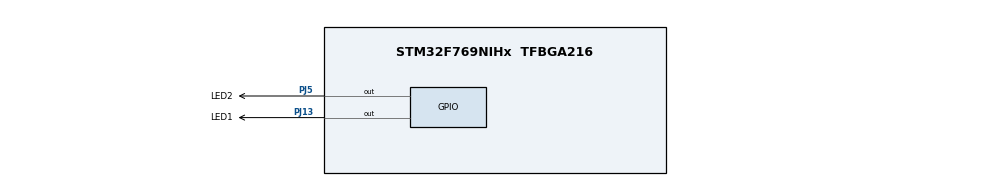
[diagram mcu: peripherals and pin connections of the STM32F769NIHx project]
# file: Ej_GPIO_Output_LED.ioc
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CORTEX_M7.ART_ACCLERATOR_ENABLE=0
CORTEX_M7.CPU_DCache=Disabled
CORTEX_M7.CPU_ICache=Disabled
CORTEX_M7.PREFETCH_ENABLE=0
Mcu.Family=STM32F7
Mcu.Name=STM32F769NIHx
Mcu.Package=TFBGA216
NVIC.PriorityGroup=NVIC_PRIORITYGROUP_4
NVIC.RCC_IRQn=true\:0\:0\:false\:false\:true\:true
PH0/OSC_IN.Mode=HSE-External-Oscillator
PH0/OSC_IN.Signal=RCC_OSC_IN
PH1/OSC_OUT.Mode=HSE-External-Oscillator
PH1/OSC_OUT.Signal=RCC_OSC_OUT
PJ13.GPIO_Label=LED1
PJ13.Signal=GPIO_Output
PJ5.GPIO_Label=LED2
PJ5.Signal=GPIO_Output
ProjectManager.HeapSize=0x200
ProjectManager.StackSize=0x400
ProjectManager.TargetToolchain=MDK-ARM V5
RCC.AHBFreq_Value=216000000
RCC.APB1CLKDivider=RCC_HCLK_DIV4
RCC.APB1Freq_Value=54000000
RCC.APB1TimFreq_Value=108000000
RCC.APB2CLKDivider=RCC_HCLK_DIV2
RCC.APB2Freq_Value=108000000
RCC.APB2TimFreq_Value=216000000
RCC.CortexFreq_Value=216000000
RCC.HCLKFreq_Value=216000000
RCC.HSE_VALUE=4000000
RCC.HSI_VALUE=16000000
RCC.LSE_VALUE=32768
RCC.PLL48CLockSelection=RCC_CLK48SOURCE_PLLSAIP
RCC.PLLDSIIDF=DSI_PLL_IN_DIV2
RCC.PLLDSINDIV=125
RCC.PLLI2SN=96
RCC.PLLM=2
RCC.PLLN=216
RCC.PLLQ=4
RCC.PLLSAIN=108
RCC.PLLSAIP=RCC_PLLSAIP_DIV6
RCC.PLLSAIQ=3
RCC.PLLSAIR=3
RCC.PLLSourceVirtual=RCC_PLLSOURCE_HSE
RCC.PLLState-ClockTree=RCC_PLL_ON
RCC.SDMMC2ClockSelection=RCC_SDMMC2CLKSOURCE_CLK48
RCC.SYSCLKFreq_VALUE=216000000
RCC.SYSCLKSource=RCC_SYSCLKSOURCE_PLLCLK
RCC.USBFreq_Value=36000000
RCC.VCOOutputFreq_Value=432000000
board=32F769IDISCOVERY

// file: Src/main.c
/**
  ******************************************************************************
  * @file           : main.c
  * @brief          : Main program body
  ******************************************************************************
  ** This notice applies to any and all portions of this file
  * that are not between comment pairs USER CODE BEGIN and
  * USER CODE END. Other portions of this file, whether
  * inserted by the user or by software development tools
  * are owned by their respective copyright owners.
  *
  * COPYRIGHT(c) 2018 STMicroelectronics
  *
  * Redistribution and use in source and binary forms, with or without modification,
  * are permitted provided that the following conditions are met:
  *   1. Redistributions of source code must retain the above copyright notice,
  *      this list of conditions and the following disclaimer.
  *   2. Redistributions in binary form must reproduce the above copyright notice,
  *      this list of conditions and the following disclaimer in the documentation
  *      and/or other materials provided with the distribution.
  *   3. Neither the name of STMicroelectronics nor the names of its contributors
  *      may be used to endorse or promote products derived from this software
  *      without specific prior written permission.
  *
  * THIS SOFTWARE IS PROVIDED BY THE COPYRIGHT HOLDERS AND CONTRIBUTORS "AS IS"
  * AND ANY EXPRESS OR IMPLIED WARRANTIES, INCLUDING, BUT NOT LIMITED TO, THE
  * IMPLIED WARRANTIES OF MERCHANTABILITY AND FITNESS FOR A PARTICULAR PURPOSE ARE
  * DISCLAIMED. IN NO EVENT SHALL THE COPYRIGHT HOLDER OR CONTRIBUTORS BE LIABLE
  * FOR ANY DIRECT, INDIRECT, INCIDENTAL, SPECIAL, EXEMPLARY, OR CONSEQUENTIAL
  * DAMAGES (INCLUDING, BUT NOT LIMITED TO, PROCUREMENT OF SUBSTITUTE GOODS OR
  * SERVICES; LOSS OF USE, DATA, OR PROFITS; OR BUSINESS INTERRUPTION) HOWEVER
  * CAUSED AND ON ANY THEORY OF LIABILITY, WHETHER IN CONTRACT, STRICT LIABILITY,
  * OR TORT (INCLUDING NEGLIGENCE OR OTHERWISE) ARISING IN ANY WAY OUT OF THE USE
  * OF THIS SOFTWARE, EVEN IF ADVISED OF THE POSSIBILITY OF SUCH DAMAGE.
  *
  ******************************************************************************
  */
#include "main.h"
#include "stm32f7xx_hal.h"

/* USER CODE BEGIN PV */
/* Private variables ---------------------------------------------------------*/

/* USER CODE END PV */

void SystemClock_Config(void);
static void MX_GPIO_Init(void);

/* USER CODE BEGIN PFP */
/* Private function prototypes -----------------------------------------------*/

/* USER CODE END PFP */

int main(void)
{

  /* MCU Configuration----------------------------------------------------------*/

  /* Reset of all peripherals, Initializes the Flash interface and the Systick. */
  HAL_Init();

  /* Configure the system clock */
  SystemClock_Config();

  /* Initialize all configured peripherals */
  MX_GPIO_Init();

  /* Infinite loop */
  /* USER CODE BEGIN WHILE */
  while (1)
  {
		HAL_GPIO_TogglePin(GPIOJ, GPIO_PIN_13);
		HAL_Delay( 250 );
		HAL_GPIO_TogglePin(GPIOJ, GPIO_PIN_5);
		HAL_Delay( 250 );
  /* USER CODE END WHILE */

  }

}

void SystemClock_Config(void)
{

  RCC_OscInitTypeDef RCC_OscInitStruct;
  RCC_ClkInitTypeDef RCC_ClkInitStruct;

    /**Configure the main internal regulator output voltage
    */
  __HAL_RCC_PWR_CLK_ENABLE();

  __HAL_PWR_VOLTAGESCALING_CONFIG(PWR_REGULATOR_VOLTAGE_SCALE1);

    /**Initializes the CPU, AHB and APB busses clocks
    */
  RCC_OscInitStruct.OscillatorType = RCC_OSCILLATORTYPE_HSE;
  RCC_OscInitStruct.HSEState = RCC_HSE_ON;
  RCC_OscInitStruct.PLL.PLLState = RCC_PLL_ON;
  RCC_OscInitStruct.PLL.PLLSource = RCC_PLLSOURCE_HSE;
  RCC_OscInitStruct.PLL.PLLM = 25;
  RCC_OscInitStruct.PLL.PLLN = 432;
  RCC_OscInitStruct.PLL.PLLP = RCC_PLLP_DIV2;
  RCC_OscInitStruct.PLL.PLLQ = 4;
  if (HAL_RCC_OscConfig(&RCC_OscInitStruct) != HAL_OK)
  {
    _Error_Handler(__FILE__, __LINE__);
  }

    /**Activate the Over-Drive mode
    */
  if (HAL_PWREx_EnableOverDrive() != HAL_OK)
  {
    _Error_Handler(__FILE__, __LINE__);
  }

    /**Initializes the CPU, AHB and APB busses clocks
    */
  RCC_ClkInitStruct.ClockType = RCC_CLOCKTYPE_HCLK|RCC_CLOCKTYPE_SYSCLK
                              |RCC_CLOCKTYPE_PCLK1|RCC_CLOCKTYPE_PCLK2;
  RCC_ClkInitStruct.SYSCLKSource = RCC_SYSCLKSOURCE_PLLCLK;
  RCC_ClkInitStruct.AHBCLKDivider = RCC_SYSCLK_DIV1;
  RCC_ClkInitStruct.APB1CLKDivider = RCC_HCLK_DIV4;
  RCC_ClkInitStruct.APB2CLKDivider = RCC_HCLK_DIV2;

  if (HAL_RCC_ClockConfig(&RCC_ClkInitStruct, FLASH_LATENCY_7) != HAL_OK)
  {
    _Error_Handler(__FILE__, __LINE__);
  }

    /**Configure the Systick interrupt time
    */
  HAL_SYSTICK_Config(HAL_RCC_GetHCLKFreq()/1000);

    /**Configure the Systick
    */
  HAL_SYSTICK_CLKSourceConfig(SYSTICK_CLKSOURCE_HCLK);

  /* SysTick_IRQn interrupt configuration */
  HAL_NVIC_SetPriority(SysTick_IRQn, 0, 0);
}

/** Configure pins as
        * Analog
        * Input
        * Output
        * EVENT_OUT
        * EXTI
*/
static void MX_GPIO_Init(void)
{

  GPIO_InitTypeDef GPIO_InitStruct;

  /* GPIO Ports Clock Enable */
  __HAL_RCC_GPIOJ_CLK_ENABLE();
  __HAL_RCC_GPIOH_CLK_ENABLE();

  /*Configure GPIO pin Output Level */
  HAL_GPIO_WritePin(GPIOJ, LED1_Pin|LED2_Pin, GPIO_PIN_RESET);

  /*Configure GPIO pins : LED1_Pin LED2_Pin */
  GPIO_InitStruct.Pin = LED1_Pin|LED2_Pin;
  GPIO_InitStruct.Mode = GPIO_MODE_OUTPUT_PP;
  GPIO_InitStruct.Pull = GPIO_NOPULL;
  GPIO_InitStruct.Speed = GPIO_SPEED_FREQ_LOW;
  HAL_GPIO_Init(GPIOJ, &GPIO_InitStruct);

}

void _Error_Handler(char *file, int line)
{
  while(1)
  {
  }
}

/************************ (C) COPYRIGHT STMicroelectronics *****END OF FILE****/
